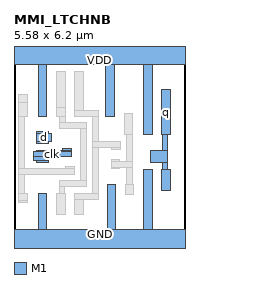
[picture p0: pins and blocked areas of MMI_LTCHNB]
MACRO MMI_LTCHNB
	CLASS CORE ;
	FOREIGN MMI_LTCHNB 0 0 ;
	SIZE 5.58 BY 6.2 ;
	SYMMETRY X Y ;
	SITE CORE1 ;
	PIN d
		DIRECTION input ;
		USE SIGNAL ;
		PORT
			LAYER M1 ;
			RECT 0.74 3.545 1.12 3.6 ;
			LAYER M1 ;
			RECT 0.74 3.265 1.235 3.545 ;
			LAYER M1 ;
			RECT 0.74 3.22 1.12 3.265 ;
		END
		AntennaGateArea 0.3465 ;
	END d
	PIN GND
		DIRECTION inout ;
		USE GROUND ;
		PORT
			LAYER M1 ;
			RECT 0.795 0.42 1.075 1.59 ;
			LAYER M1 ;
			RECT 3.04 0.42 3.32 1.875 ;
			LAYER M1 ;
			RECT 4.225 0.42 4.505 2.38 ;
			LAYER M1 ;
			RECT 0 -0.42 5.58 0.42 ;
		END
	END GND
	PIN q
		DIRECTION output ;
		USE SIGNAL ;
		PORT
			LAYER M1 ;
			RECT 4.825 3.505 5.105 4.975 ;
			LAYER M1 ;
			RECT 4.83 2.98 5.02 3.505 ;
			LAYER M1 ;
			RECT 4.46 2.6 5.02 2.98 ;
			LAYER M1 ;
			RECT 4.83 2.38 5.02 2.6 ;
			LAYER M1 ;
			RECT 4.815 1.68 5.095 2.38 ;
		END
		AntennaDiffArea 0.91245 ;
	END q
	PIN VDD
		DIRECTION inout ;
		USE POWER ;
		PORT
			LAYER M1 ;
			RECT 0 5.78 5.58 6.62 ;
			LAYER M1 ;
			RECT 0.795 4.105 1.075 5.78 ;
			LAYER M1 ;
			RECT 3 4.105 3.28 5.78 ;
			LAYER M1 ;
			RECT 4.235 3.505 4.515 5.78 ;
		END
	END VDD
	PIN clk
		DIRECTION input ;
		USE CLOCK ;
		PORT
			LAYER M1 ;
			RECT 1.595 2.98 1.875 3.065 ;
			LAYER M1 ;
			RECT 0.74 2.94 1.875 2.98 ;
			LAYER M1 ;
			RECT 0.62 2.785 1.875 2.94 ;
			LAYER M1 ;
			RECT 0.62 2.66 1.12 2.785 ;
			LAYER M1 ;
			RECT 0.74 2.6 1.12 2.66 ;
		END
		AntennaGateArea 0.45675 ;
	END clk
	OBS
		LAYER M1 ;
		RECT 0.16 4.565 0.44 4.805 ;
		LAYER M1 ;
		RECT 0.15 4.105 0.44 4.565 ;
		LAYER M1 ;
		RECT 1.385 4.4 1.665 5.575 ;
		LAYER M1 ;
		RECT 1.385 4.105 1.675 4.4 ;
		LAYER M1 ;
		RECT 1.975 4.295 2.255 5.575 ;
		LAYER M1 ;
		RECT 1.975 4.105 2.765 4.295 ;
		LAYER M1 ;
		RECT 0.15 2.395 0.345 4.105 ;
		LAYER M1 ;
		RECT 1.485 3.9 1.675 4.105 ;
		LAYER M1 ;
		RECT 1.485 3.71 2.37 3.9 ;
		LAYER M1 ;
		RECT 1.695 2.395 1.975 2.48 ;
		LAYER M1 ;
		RECT 0.15 2.2 1.975 2.395 ;
		LAYER M1 ;
		RECT 0.15 1.59 0.345 2.2 ;
		LAYER M1 ;
		RECT 2.18 1.995 2.37 3.71 ;
		LAYER M1 ;
		RECT 1.47 1.8 2.37 1.995 ;
		LAYER M1 ;
		RECT 2.575 3.265 2.765 4.105 ;
		LAYER M1 ;
		RECT 3.595 3.505 3.875 4.205 ;
		LAYER M1 ;
		RECT 3.185 3.265 3.465 3.295 ;
		LAYER M1 ;
		RECT 2.575 3.07 3.465 3.265 ;
		LAYER M1 ;
		RECT 1.47 1.59 1.66 1.8 ;
		LAYER M1 ;
		RECT 0.15 1.365 0.44 1.59 ;
		LAYER M1 ;
		RECT 0.16 1.275 0.44 1.365 ;
		LAYER M1 ;
		RECT 1.385 0.89 1.665 1.59 ;
		LAYER M1 ;
		RECT 1.975 1.57 2.255 1.59 ;
		LAYER M1 ;
		RECT 2.575 1.57 2.765 3.07 ;
		LAYER M1 ;
		RECT 3.185 3.015 3.465 3.07 ;
		LAYER M1 ;
		RECT 3.175 2.635 3.455 2.685 ;
		LAYER M1 ;
		RECT 3.67 2.635 3.865 3.505 ;
		LAYER M1 ;
		RECT 3.175 2.445 3.865 2.635 ;
		LAYER M1 ;
		RECT 3.175 2.405 3.455 2.445 ;
		LAYER M1 ;
		RECT 3.67 1.875 3.865 2.445 ;
		LAYER M1 ;
		RECT 1.975 1.38 2.765 1.57 ;
		LAYER M1 ;
		RECT 1.975 0.89 2.255 1.38 ;
		LAYER M1 ;
		RECT 3.63 1.56 3.91 1.875 ;
	END
END MMI_LTCHNB
